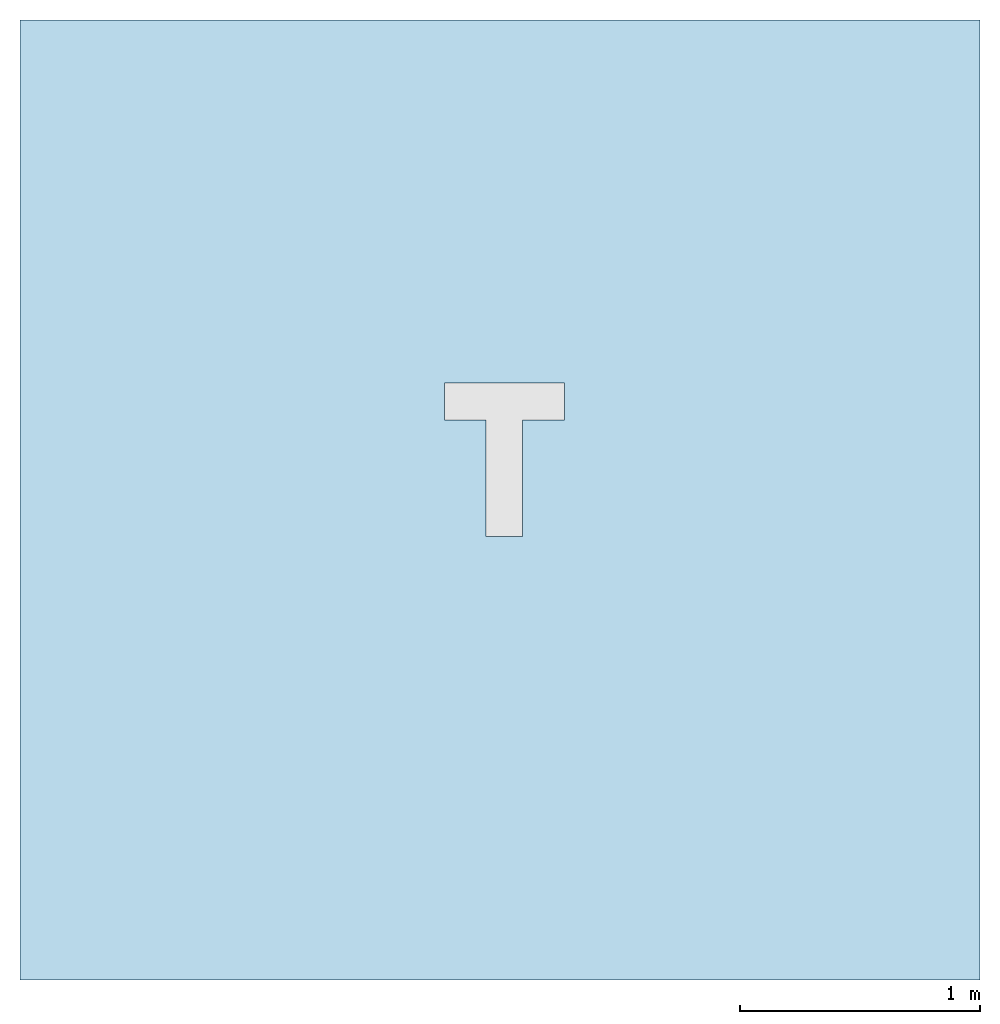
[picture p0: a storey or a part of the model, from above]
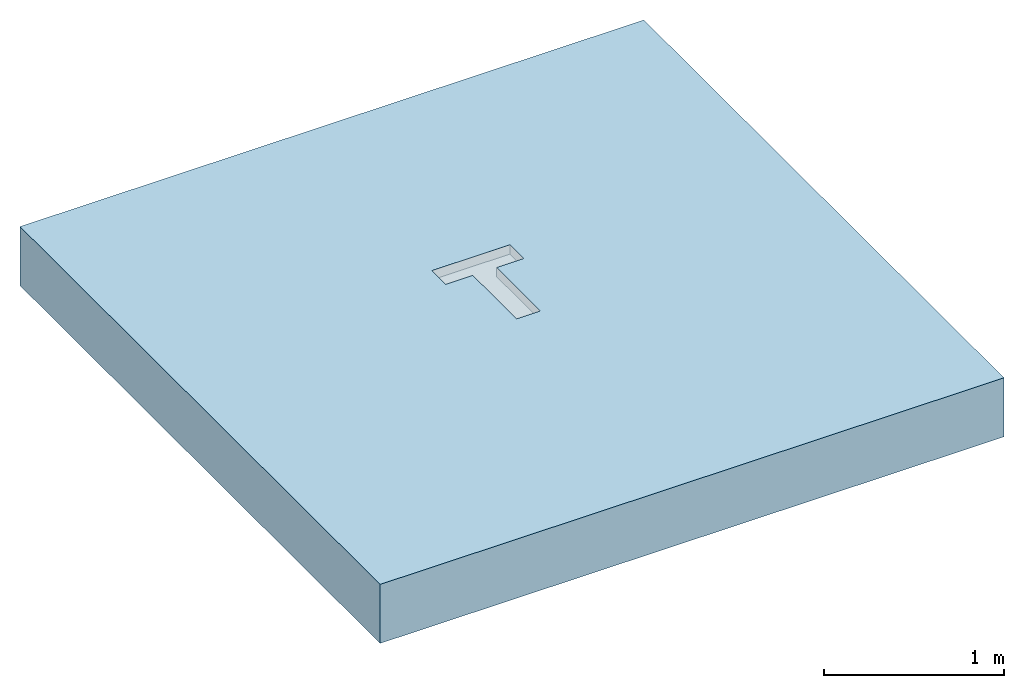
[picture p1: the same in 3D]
Properties of the parts of a building model (IFC2X3)

# File
Description: ViewDefinition [CoordinationView]
File name: 105221 - Branch Unit Channel - 500mm LG - Invert Depth 50mm.ifc
Time: 2014-03-20T10:26:55
Written by: Autodesk Revit 2013
Made in: 20120221_2030(x64)

# IfcProject, Project Number
LongName: Project Name; Phase: Project Status

# IfcSite, Default
RefLatitude: 42, 21, 30, 344238; RefLongitude: -71, -3, -35, -194702; RefElevation: 0 mm

# IfcBuilding
Pset_BuildingCommon - NumberOfStoreys: 1
Other - Project Address: ## Street City, State Zip; Project Number: Project Number; Project Issue Date: Issue Date; Project Name: Project Name; Project Status: Project Status; Client Name: Owner

# IfcBuildingStorey, Level 1
LongName: Level 1; Elevation: 0 mm
Constraints - Elevation Base: 0; Elevation: 0 mm
Graphics - Line Weight: 1; Color: 0; Line Pattern: Center; Symbol at End 2 Default: yes; Symbol at End 1 Default: no; Symbol: M_Level Head - Circle: M_Level Head - Circle
Dimensions - Computation Height: 0 mm
Identity Data - Structural: no; Building Story: yes; Name: Level 1

# IfcFlowTerminal: 105221 - Branch Unit Channel - 500mm LG - Invert Depth 50mm, ACO BD Modular 125 Branch Units:105221 - Branch Unit Channel - 500mm LG - Invert Depth 50mm:105221 - Branch Unit Channel - 500mm LG - Invert Depth 50mm:216444
In: Level 1
Material: Stainless Steel AISI 304 (F), Polystyrene, High Impact
Construction - 105521 - Slotted Locked - Stainless Steel 304 - 500mm long: no; 49061 & 49062_Vinyl Seal: no; End Plate Invert: no; 105505 - Perforated Locked - Stainless Steel 304 - 500mm long: no; 21790 - Plastic - White Plastic - 500mm long: no; 105530 - Quadrato - Stainless Steel 304 - 500mm long: no; End Plate Invert Right Hand: no; 105528 - Quadrato Locked - Stainless Steel 304 - 500mm long: no; 105537 - Intercept Locked - Stainless Steel 304 - 500mm long: no; 26270_PVC Infill: yes; 21720 - Grating - Plain Mesh - Stainless Steel 304 - 500mm long: no; 105846 - Slip Resistant Intercept - Stainless Steel 304 - 500mm long: no; 105519 - Slotted Locked - Stainless Steel 304 - 500mm long: no; 21910 - Grating - Slip Resistant Mesh - Stainless Steel 304 - 500mm long: no; 105539 - Intercept - Stainless Steel 304 - 500mm long: no; 402072- Grating - Heal Safe Locked - Stainless Steel 304 - 500mm long: no; 15704 - Composite - Black Composite - 500mm long: no; 10735 - Composite - White Composite - 500mm long: no; 21920 - Grating - Plain Mesh - Stainless Steel 304 - 500mm long: no; 105842 - Slip Resistant Quadrato - Stainless Steel 304 - 500mm long: no; 96819 - Grating - Heal Safe - Stainless Steel 304 - 500mm long: no; 21740 - - Ladder - Stainless Steel 304 - 500mm long: no; 105848 - Slip Resistant Intercept Locked - Stainless Steel 304 - 500mm long: no; 21710 - Grating - Slip Resistant Mesh - Stainless Steel 304 - 500mm long: no; End Plate Invert Left Hand: no; 105844 - Slip Resistant Quadrato Locked - Stainless Steel 304 - 500mm long: no; Grating: yes; Detail 125mm: no; Detail 50mm: yes; Detail 65mm: no; Detail 110mm: no; Detail 95mm: no; Detail 80mm: no
Other - PVC Infill (26270): 1847 mm; Neoprene Gasket: 2; Flexible PVC Seal (49062): 0 mm; Rigid PVC Extrusion (49061): 0 mm
Phasing - Phase Created: New Construction
Dimensions - Void Invert Depth: 62.8 mm; Depth: 29 mm; Invert Depth: 50 mm; Grating Height: 21 mm
Identity Data - Mark: 3; Manufacturer: ACO Building Drainage; Fax: +44 (0)1462 851490; Telephone: +44 (0)1462 816666; Address: ACO Business Centre, Caxton Road, Bedford, MK41 0LF; Watermarked With: BIM Manager Premium Suite; Watermark1: This file is the property of ACO Technologies PLC; Watermark2: This file is water marked and users are prohibited to reproduce, adapt, distribute this information; Watermarked By: www.acobd.com; E-mail Technical: abdtechnical@aco.co.uk; E-mail Sales: abdcommercial@aco.co.uk; Website: www.acobd.com
Constraints - Level: Level: Level 1; Moves With Nearby Elements: no
Model Properties - Grating Product Code 21910: Load Class C250 - Slip Resistant Mesh - Stainless Steel 304 - 500mm long - 2.2kg; Grating Product Code 105848: Load Class A15 - Slip Resistant Intercept Locked - Stainless Steel 304 - 500mm long - 1.8kg; Grating Product Code 21740: Load Class C250 - Ladder - Stainless Steel 304 - 500mm long - 2.0kg; End Plate Product Code 105103: N/A; Grating Product Code 105530: Load Class A15 - Quadrato - Stainless Steel 304 - 500mm long - 1.6kg; Grating Product Code 96819: Load Class B125 - Heal Safe - Stainless Steel 304 - 500mm long - 2.0kg; Grating Product Code 105505: Load Class C250 - Perforated Locked - Stainless Steel 304 - 500mm long - 1.8kg; Grating Product Code 21920: Load Class C250 - Plain Mesh - Stainless Steel 304 - 500mm long - 2.2kg; Grating Product Code 105519: Load Class A15 - Slotted Locked - Stainless Steel 304 - 500mm long - 1.0kg; End Plate Product Code 105105: N/A; Grating Product Code 105844: Load Class A15 - Slip Resistant Quadrato Locked - Stainless Steel 304 - 500mm long - 1.6kg; Grating Product Code 105521: Load Class C250 - Slotted Locked - Stainless Steel 304 - 500mm long - 2.3kg; Grating Product Code 21790: Load Class A15 - Plastic - White Plastic - 500mm long - 0.6kg; End Plate Product Code 105104: N/A; Grating Product Code 105846: Load Class A15 - Slip Resistant Intercept - Stainless Steel 304 - 500mm long - 1.8kg; End Plate Product Code 105101: N/A; Grating Product Code 105842: Load Class A15 - Slip Resistant Quadrato - Stainless Steel 304 - 500mm long - 1.6kg; Grating Product Code 21720: Load Class A15 - Plain Mesh - Stainless Steel 304 - 500mm long - 1.6kg; End Plate Product Code 105100: End Plate Stainless Steel 304 for Invert Depth - 50mm - 0.2Kg; Grating Product Code 105539: Load Class A15 - Intercept - Stainless Steel 304 - 500mm long - 1.8kg; Grating Product Code 10735: Load Class C250 - Composite - White Composite - 500mm long - 1.2kg; End Plate Product Code 105102: N/A; Grating Product Code 105537: Load Class A15 - Intercept Locked - Stainless Steel 304 - 500mm long - 1.8kg; Grating Product Code 402072: Load Class B125 - Heal Safe Locked - Stainless Steel 304 - 500mm long - 2.0kg; Grating Product Code 105528: Load Class A15 - Quadrato Locked - Stainless Steel 304 - 500mm long - 1.6kg; Grating Product Code 15704: Load Class C250 - Composite - Black Composite - 500mm long - 1.2kg; Grating Product Code 21710: Load Class A15 - Slip Resistant Mesh - Stainless Steel 304 - 500mm long - 1.6kg
General - Product Description: ACO Modular 125 500mm Branch Unit; Dimensions (LxWxH): 500 x 639 x 50; Maintenance guidelines: X:\Electronic Literature\ABD Electronic Literature\Standard Stainless Steel and Galvanised Steel Channels\ACO Modular 125\ACO Modular 125.pdf; NBS Specification: NBS Section Q10 Kerbs/edgings/channels/paving accessories, Clause 180 Drainage Channel Systems; Product Range: ACO Modular 125; Channel Material: Stainless Steel Grade 304; Seal Colour: Black; Channel Colour: Mid Grey; Channel Recyclable: Fully recyclable; Installation guidelines: X:\Electronic Literature\ABD Electronic Literature\Standard Stainless Steel and Galvanised Steel Channels\ACO Modular 125\ACO Modular 125.pdf; Channel Recycled Material Content: 60-70%; Product Code: 105221; Price: POA - contact ACO; Seal Recycled Material Content: 0%; Product Type: Stainless Steel Channel Drainage System; Seal Material: Neoprene; Weight (Kg): 3.9; Seal Recyclable: Fully recyclable; Product Standard: BS EN 1433:2002, CE marked; Load Class: A15 - C250

# IfcOpeningElement: Recess
In: Level 1
Dimensions - Thickness: 400 mm; Area: 16000000 mm2; Volume: 6390526116 mm3; Perimeter: 16000 mm
Structural - Structural: no; Enable Analytical Model: no
Constraints - Room Bounding: yes; Level: Level: Level 1; Related to Mass: no; Height Offset From Level: 0 mm
Phasing - Phase Created: New Construction
Materials and Finishes - Structural Material: Concrete, Broom Finish
Graphics - Coarse Scale Fill Color: 0
Construction - Function: 0; Default Thickness: 400 mm
Analytical Properties - Thermal Resistance (R): 0.382409; Thermal mass: 604440; Heat Transfer Coefficient (U): 2.615; Roughness: 1; Absorptance: 0.1

# IfcSlab: Floor:Generic Floor - 400mm, Floor:Generic Floor - 400mm:193825
In: Level 1
PredefinedType: FLOOR; Material: Concrete, Broom Finish 400 mm
Dimensions - Thickness: 400 mm; Area: 16000000 mm2; Volume: 6390526116 mm3; Perimeter: 16000 mm
Structural - Structural: no; Enable Analytical Model: no
Constraints - Room Bounding: yes; Level: Level: Level 1; Related to Mass: no; Height Offset From Level: 0 mm
Phasing - Phase Created: New Construction
Pset_SlabCommon - Reference: Generic Floor - 400mm; IsExternal: no; LoadBearing: yes
Materials and Finishes - Structural Material: Concrete, Broom Finish
Graphics - Coarse Scale Fill Color: 0
Construction - Function: 0; Default Thickness: 400 mm
Analytical Properties - Thermal Resistance (R): 0.382409; Thermal mass: 604440; Heat Transfer Coefficient (U): 2.615; Roughness: 1; Absorptance: 0.1
